One B-rep face of a CAD part: STEP entity #303.
In plain terms, the planar face has unit normal (1, 0, 0).
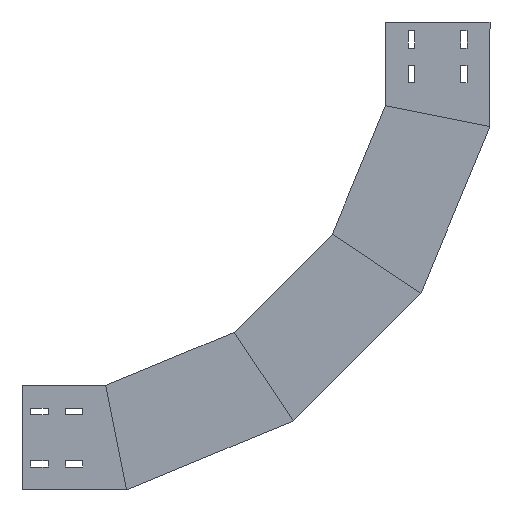
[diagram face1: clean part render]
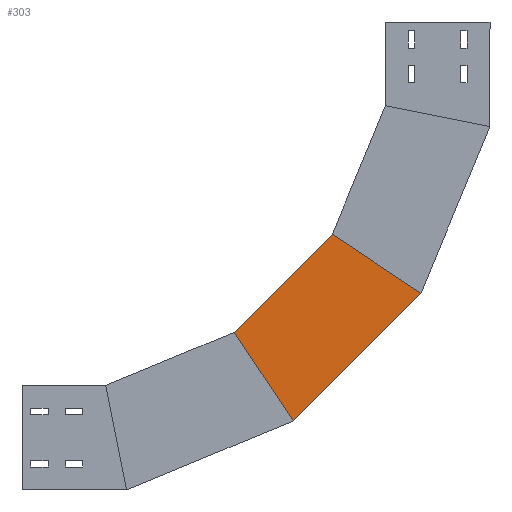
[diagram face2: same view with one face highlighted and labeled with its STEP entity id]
Its self-contained STEP definition (entity closure, numbers rounded to 3 decimals):
#199 = VECTOR ( 'NONE', #2120, 1000. ) ;
#255 = DIRECTION ( 'NONE',  ( 0., 0.707, -0.707 ) ) ;
#285 = CARTESIAN_POINT ( 'NONE',  ( 0., 99.115, -389.285 ) ) ;
#294 = ORIENTED_EDGE ( 'NONE', *, *, #1491, .F. ) ;
#303 = ADVANCED_FACE ( 'NONE', ( #2280 ), #983, .F. ) ;
#336 = EDGE_CURVE ( 'NONE', #1277, #1611, #407, .T. ) ;
#407 = LINE ( 'NONE', #1393, #199 ) ;
#431 = VECTOR ( 'NONE', #2313, 1000. ) ;
#440 = AXIS2_PLACEMENT_3D ( 'NONE', #643, #1173, #1213 ) ;
#624 = ORIENTED_EDGE ( 'NONE', *, *, #1705, .T. ) ;
#643 = CARTESIAN_POINT ( 'NONE',  ( 0., 99.115, -389.285 ) ) ;
#744 = EDGE_CURVE ( 'NONE', #1277, #2110, #1709, .T. ) ;
#825 = CARTESIAN_POINT ( 'NONE',  ( 0., 205.181, -283.219 ) ) ;
#958 = VECTOR ( 'NONE', #255, 1000. ) ;
#983 = PLANE ( 'NONE',  #440 ) ;
#1158 = VERTEX_POINT ( 'NONE', #2426 ) ;
#1173 = DIRECTION ( 'NONE',  ( -1., 0., 0. ) ) ;
#1213 = DIRECTION ( 'NONE',  ( 0., 0., 1. ) ) ;
#1249 = ORIENTED_EDGE ( 'NONE', *, *, #336, .T. ) ;
#1277 = VERTEX_POINT ( 'NONE', #1913 ) ;
#1285 = CARTESIAN_POINT ( 'NONE',  ( 0., 310.328, -530.413 ) ) ;
#1354 = DIRECTION ( 'NONE',  ( 0., -0.556, -0.831 ) ) ;
#1393 = CARTESIAN_POINT ( 'NONE',  ( 0., 141.128, -361.213 ) ) ;
#1399 = EDGE_LOOP ( 'NONE', ( #2039, #1249, #624, #294 ) ) ;
#1436 = CARTESIAN_POINT ( 'NONE',  ( 0., 367.224, -445.262 ) ) ;
#1491 = EDGE_CURVE ( 'NONE', #2110, #1158, #1666, .T. ) ;
#1611 = VERTEX_POINT ( 'NONE', #285 ) ;
#1666 = LINE ( 'NONE', #1285, #2010 ) ;
#1705 = EDGE_CURVE ( 'NONE', #1611, #1158, #1761, .T. ) ;
#1709 = LINE ( 'NONE', #825, #431 ) ;
#1761 = LINE ( 'NONE', #1947, #958 ) ;
#1913 = CARTESIAN_POINT ( 'NONE',  ( 0., 226.279, -304.317 ) ) ;
#1947 = CARTESIAN_POINT ( 'NONE',  ( 0., 99.115, -389.285 ) ) ;
#2010 = VECTOR ( 'NONE', #1354, 1000. ) ;
#2039 = ORIENTED_EDGE ( 'NONE', *, *, #744, .F. ) ;
#2110 = VERTEX_POINT ( 'NONE', #1436 ) ;
#2120 = DIRECTION ( 'NONE',  ( 0., -0.831, -0.556 ) ) ;
#2280 = FACE_OUTER_BOUND ( 'NONE', #1399, .T. ) ;
#2313 = DIRECTION ( 'NONE',  ( 0., 0.707, -0.707 ) ) ;
#2426 = CARTESIAN_POINT ( 'NONE',  ( 0., 282.256, -572.425 ) ) ;
